VERSION 5.7 ;
  NOWIREEXTENSIONATPIN ON ;
  DIVIDERCHAR "/" ;
  BUSBITCHARS "[]" ;
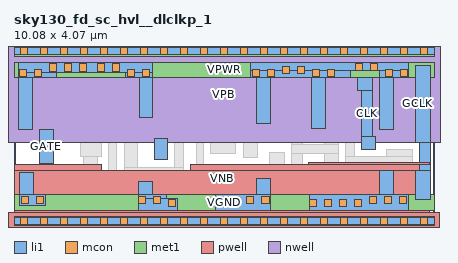
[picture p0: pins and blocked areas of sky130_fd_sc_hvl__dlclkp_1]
MACRO sky130_fd_sc_hvl__dlclkp_1
  CLASS BLOCK ;
  FOREIGN sky130_fd_sc_hvl__dlclkp_1 ;
  ORIGIN 0.000 0.000 ;
  SIZE 10.080 BY 4.070 ;
  PIN CLK
    ANTENNAGATEAREA 1.170000 ;
    PORT
      LAYER li1 ;
        RECT 8.235 3.125 8.600 3.445 ;
        RECT 8.350 2.025 8.600 3.125 ;
        RECT 3.360 1.465 3.690 1.975 ;
        RECT 8.350 1.725 8.680 2.025 ;
    END
  END CLK
  PIN GATE
    ANTENNAGATEAREA 0.585000 ;
    PORT
      LAYER li1 ;
        RECT 0.610 1.385 0.940 2.200 ;
    END
  END GATE
  PIN VGND
    USE GROUND ;
    PORT
      LAYER li1 ;
        RECT 0.140 0.625 0.470 1.170 ;
        RECT 2.980 0.625 3.330 0.955 ;
        RECT 5.820 0.625 6.150 1.025 ;
        RECT 8.770 0.625 9.100 1.215 ;
        RECT 0.140 0.365 0.765 0.625 ;
        RECT 2.980 0.535 3.650 0.625 ;
        RECT 2.980 0.255 3.925 0.535 ;
        RECT 4.830 0.255 6.150 0.625 ;
        RECT 7.080 0.255 9.460 0.625 ;
      LAYER mcon ;
        RECT 0.175 0.425 0.345 0.595 ;
        RECT 0.535 0.425 0.705 0.595 ;
        RECT 2.995 0.425 3.165 0.595 ;
        RECT 3.355 0.425 3.525 0.595 ;
        RECT 3.715 0.355 3.885 0.525 ;
        RECT 4.870 0.355 5.040 0.525 ;
        RECT 5.230 0.355 5.400 0.525 ;
        RECT 5.590 0.425 5.760 0.595 ;
        RECT 5.950 0.425 6.120 0.595 ;
        RECT 7.100 0.355 7.270 0.525 ;
        RECT 7.460 0.355 7.630 0.525 ;
        RECT 7.820 0.355 7.990 0.525 ;
        RECT 8.180 0.355 8.350 0.525 ;
        RECT 8.540 0.425 8.710 0.595 ;
        RECT 8.900 0.425 9.070 0.595 ;
        RECT 9.260 0.425 9.430 0.595 ;
      LAYER met1 ;
        RECT 0.000 0.255 10.080 0.625 ;
    END
  END VGND
  PIN VNB
    ANTENNADIFFAREA 1.713600 ;
    PORT
      LAYER pwell ;
        RECT 8.680 1.405 9.970 1.415 ;
        RECT 7.060 1.345 9.970 1.405 ;
        RECT 0.020 1.210 2.090 1.345 ;
        RECT 4.240 1.210 9.970 1.345 ;
        RECT 0.020 0.215 9.970 1.210 ;
        RECT -0.130 -0.215 10.210 0.215 ;
      LAYER li1 ;
        RECT 0.000 -0.085 10.080 0.085 ;
      LAYER mcon ;
        RECT 0.155 -0.085 0.325 0.085 ;
        RECT 0.635 -0.085 0.805 0.085 ;
        RECT 1.115 -0.085 1.285 0.085 ;
        RECT 1.595 -0.085 1.765 0.085 ;
        RECT 2.075 -0.085 2.245 0.085 ;
        RECT 2.555 -0.085 2.725 0.085 ;
        RECT 3.035 -0.085 3.205 0.085 ;
        RECT 3.515 -0.085 3.685 0.085 ;
        RECT 3.995 -0.085 4.165 0.085 ;
        RECT 4.475 -0.085 4.645 0.085 ;
        RECT 4.955 -0.085 5.125 0.085 ;
        RECT 5.435 -0.085 5.605 0.085 ;
        RECT 5.915 -0.085 6.085 0.085 ;
        RECT 6.395 -0.085 6.565 0.085 ;
        RECT 6.875 -0.085 7.045 0.085 ;
        RECT 7.355 -0.085 7.525 0.085 ;
        RECT 7.835 -0.085 8.005 0.085 ;
        RECT 8.315 -0.085 8.485 0.085 ;
        RECT 8.795 -0.085 8.965 0.085 ;
        RECT 9.275 -0.085 9.445 0.085 ;
        RECT 9.755 -0.085 9.925 0.085 ;
      LAYER met1 ;
        RECT 0.000 -0.115 10.080 0.115 ;
    END
  END VNB
  PIN VPB
    ANTENNADIFFAREA 1.713600 ;
    PORT
      LAYER nwell ;
        RECT -0.330 1.885 10.410 4.485 ;
      LAYER li1 ;
        RECT 0.000 3.985 10.080 4.155 ;
      LAYER mcon ;
        RECT 0.155 3.985 0.325 4.155 ;
        RECT 0.635 3.985 0.805 4.155 ;
        RECT 1.115 3.985 1.285 4.155 ;
        RECT 1.595 3.985 1.765 4.155 ;
        RECT 2.075 3.985 2.245 4.155 ;
        RECT 2.555 3.985 2.725 4.155 ;
        RECT 3.035 3.985 3.205 4.155 ;
        RECT 3.515 3.985 3.685 4.155 ;
        RECT 3.995 3.985 4.165 4.155 ;
        RECT 4.475 3.985 4.645 4.155 ;
        RECT 4.955 3.985 5.125 4.155 ;
        RECT 5.435 3.985 5.605 4.155 ;
        RECT 5.915 3.985 6.085 4.155 ;
        RECT 6.395 3.985 6.565 4.155 ;
        RECT 6.875 3.985 7.045 4.155 ;
        RECT 7.355 3.985 7.525 4.155 ;
        RECT 7.835 3.985 8.005 4.155 ;
        RECT 8.315 3.985 8.485 4.155 ;
        RECT 8.795 3.985 8.965 4.155 ;
        RECT 9.275 3.985 9.445 4.155 ;
        RECT 9.755 3.985 9.925 4.155 ;
      LAYER met1 ;
        RECT 0.000 3.955 10.080 4.185 ;
    END
  END VPB
  PIN VPWR
    USE POWER ;
    PORT
      LAYER li1 ;
        RECT 0.110 3.555 3.330 3.815 ;
        RECT 0.110 3.445 1.025 3.555 ;
        RECT 2.665 3.445 3.330 3.555 ;
        RECT 5.685 3.615 9.460 3.815 ;
        RECT 5.685 3.445 8.065 3.615 ;
        RECT 8.770 3.445 9.460 3.615 ;
        RECT 0.110 2.200 0.440 3.445 ;
        RECT 3.000 2.485 3.330 3.445 ;
        RECT 5.820 2.330 6.150 3.445 ;
        RECT 7.150 2.225 7.480 3.445 ;
        RECT 8.770 2.195 9.100 3.445 ;
      LAYER mcon ;
        RECT 0.140 3.475 0.310 3.645 ;
        RECT 0.500 3.475 0.670 3.645 ;
        RECT 0.860 3.600 1.030 3.770 ;
        RECT 1.220 3.600 1.390 3.770 ;
        RECT 1.580 3.600 1.750 3.770 ;
        RECT 1.995 3.600 2.165 3.770 ;
        RECT 2.355 3.600 2.525 3.770 ;
        RECT 2.715 3.475 2.885 3.645 ;
        RECT 3.075 3.475 3.245 3.645 ;
        RECT 5.715 3.475 5.885 3.645 ;
        RECT 6.075 3.475 6.245 3.645 ;
        RECT 6.435 3.545 6.605 3.715 ;
        RECT 6.795 3.545 6.965 3.715 ;
        RECT 7.155 3.475 7.325 3.645 ;
        RECT 7.515 3.475 7.685 3.645 ;
        RECT 8.195 3.615 8.365 3.785 ;
        RECT 8.555 3.615 8.725 3.785 ;
        RECT 8.915 3.475 9.085 3.645 ;
        RECT 9.275 3.475 9.445 3.645 ;
      LAYER met1 ;
        RECT 0.000 3.445 10.080 3.815 ;
    END
  END VPWR
  PIN GCLK
    ANTENNADIFFAREA 0.596250 ;
    PORT
      LAYER li1 ;
        RECT 9.630 1.895 9.995 3.735 ;
        RECT 9.725 1.215 9.995 1.895 ;
        RECT 9.630 0.515 9.995 1.215 ;
    END
  END GCLK
  OBS
      LAYER li1 ;
        RECT 3.520 3.385 5.515 3.555 ;
        RECT 1.195 3.165 2.495 3.385 ;
        RECT 1.670 1.885 2.000 2.995 ;
        RECT 2.275 2.315 2.495 3.165 ;
        RECT 3.520 2.315 3.690 3.385 ;
        RECT 2.275 2.145 3.690 2.315 ;
        RECT 3.860 3.005 5.175 3.215 ;
        RECT 1.595 1.555 2.105 1.885 ;
        RECT 1.670 0.840 2.000 1.555 ;
        RECT 2.275 1.080 2.470 2.145 ;
        RECT 2.220 0.705 2.470 1.080 ;
        RECT 2.640 1.295 2.970 1.965 ;
        RECT 3.860 1.295 4.070 3.005 ;
        RECT 2.640 1.125 4.070 1.295 ;
        RECT 1.155 0.535 1.865 0.670 ;
        RECT 2.640 0.535 2.810 1.125 ;
        RECT 3.820 0.705 4.070 1.125 ;
        RECT 4.375 2.330 4.660 2.660 ;
        RECT 5.345 2.595 5.515 3.385 ;
        RECT 5.135 2.425 5.515 2.595 ;
        RECT 4.375 1.365 4.545 2.330 ;
        RECT 5.135 1.945 5.305 2.425 ;
        RECT 6.660 2.085 6.930 2.660 ;
        RECT 4.715 1.615 5.305 1.945 ;
        RECT 5.515 1.875 6.930 2.085 ;
        RECT 5.515 1.535 5.845 1.875 ;
        RECT 6.660 1.825 6.930 1.875 ;
        RECT 7.455 1.825 7.785 2.055 ;
        RECT 6.125 1.365 6.490 1.655 ;
        RECT 4.375 1.195 6.490 1.365 ;
        RECT 4.375 0.535 4.660 1.195 ;
        RECT 1.155 0.365 2.810 0.535 ;
        RECT 4.095 0.255 4.660 0.535 ;
        RECT 6.320 0.670 6.490 1.195 ;
        RECT 6.660 1.615 7.785 1.825 ;
        RECT 6.660 0.840 6.930 1.615 ;
        RECT 7.455 1.385 7.785 1.615 ;
        RECT 7.955 1.555 8.180 2.955 ;
        RECT 8.945 1.555 9.555 1.725 ;
        RECT 7.955 1.385 9.555 1.555 ;
        RECT 7.955 1.215 8.180 1.385 ;
        RECT 7.150 0.885 8.180 1.215 ;
        RECT 6.320 0.355 6.910 0.670 ;
  END
END sky130_fd_sc_hvl__dlclkp_1
END LIBRARY

